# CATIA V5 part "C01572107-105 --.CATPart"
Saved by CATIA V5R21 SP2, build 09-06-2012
Part number: C01572107-105
Revision: ---
Description: PROPRIETARY NOTICE (do not delete / modify)  ***************************************************************************************************  LA SOCIETE EN COMMANDITE  AIRBUS CANADA  ("AIRBUS CANADA")  PAR  L'INTERMEDIAIRE  DE  SES  DIVISIONS  ET/OU  FILIALES  CORPORATIVES,  FOURNIT  LES PRESENTES  INFORMATIONS  AU  GOUVERNEMENT  A  TITRE CONFIDENTIEL. CES  INFORMATIONS ONT UNE TENEUR CONFIDENTIELLE,  AVEC DROITS DE PROPRIETE,  ET NOUS LES CONSIDERONS  EXCLUS  DE   L'APPLICATION  DE  LA LOI SUR L'ACCES A L'INFORMATION  (CANADA),  LES  LOIS  SUR  L'ACCES  A  L'INFORMATION  EUROPEENNES,  LE FREEDOM OF INFORMATION ACT (ETATS-UNIS) ET D'AUTRES LOIS SEMBLABLES. ELLES  PEUVENT  AUSSI  CONSTITUER DES SECRETS INDUSTRIELS DE NOTRE SOCIETE OU DE TIERCES PARTIES. LA DIVULGATION  PUBLIQUE  DE CES  INFORMATIONS NUIRAIT A AIRBUS CANADA OU A DES TIERCES PARTIES.  CES INFORMATIONS PEUVENT EGALEMENT CONTENIR  DES DONNEES QUI SONT CONTROLEE PAR DES LOIS DE CONTROLE DES EXPORTATIONS DU CANADA, L’EUROPE OU LES  ETATS-  UNIS. TOUTE EXPORTATION OU REEXPORTATION DE DONNEES CONTROLEES SANS AUTORISATION EST STRICTEMENT INTERDITE.  TOUTE INTENTION DE LES DIVULGUER EN TOUT OU EN PARTIE DEVRA ETRE SIGNIFIEE A L'AVANCE ET PAR ECRIT AU VICE-  PRESIDENT, SERVICES JURIDIQUES ET CONFORMITE ET SECRETAIRE CORPORATIF D'AIRBUS CANADA.    AIRBUS CANADA LIMITED PARTNERSHIP  ("AIRBUS CANADA"),  BY ITS AFFILIATES AND/OR SUBSIDIARIES, PROVIDES THIS  INFORMATION TO THE GOVERNMENT IN CONFIDENCE. THIS IS PROPRIETARY CONFIDENTIAL INFORMATION WHICH WE CONSIDER  EXCLUDED  FROM  THE  APPLICATION OF THE ACCESS TO INFORMATION ACT (CANADA),  THE FREEDOM OF INFORMATION ACT  (U.S.A.),  THE ACCESS TO INFORMATION LAWS IN EUROPE, AND OTHER SIMILAR LEGISLATION. AND MAY ALSO CONSTITUTE  TRADE SECRETS OF OUR  COMPANY OR THIRD PARTIES.  PUBLIC  RELEASE  OF  THIS INFORMATION  WOULD BE HARMFUL TO  AIRBUS CANADA OR THIRD PARTIES.  THIS  INFORMATION  MAY  ALSO  CONTAIN DATA THAT IS CONTROLLED BY CANADIAN,  EUROPEAN, OR U.S.A. EXPORT CONTROL LAWS. ANY UNAUTHORIZED EXPORT OR RE-EXPORT OF ANY EXPORT CONTROLLED DATA  IS STRICTLY PROHIBITED  ANY INTENTION TO DISCLOSE SUCH INFORMATION,  OR  PART THEREOF,  MUST BE NOTIFIED IN  ADVANCE AND IN WRITING TO THE VICE PRESIDENT, LEGAL AND COMPLIANCE AND CORPORATE SECRETARY OF AIRBUS CANADA.        LES RENSEIGNEMENTS,  LES DONNEES  ET  DESSINS  TECHNIQUES  DIVULGUES  DANS  LES PRESENTES SONT LA PROPRIETE  EXCLUSIVE DE LA SOCIETE EN COMMANDITE AIRBUS CANADA ("AIRBUS CANADA") OU COMPORTENT DES DROITS DE PROPRIETE  APPARTENANT  A  AUTRUI ET NE PEUVENT ETRE DIVULGUES  A  QUICONQUE  NI  UTILISES PAR QUI QUE CE SOIT SANS LE  CONSENTEMENT  ECRIT  D’AIRBUS  CANADA.  LE DETENTEUR DES  PRESENTES  S'ENGAGE, DANS TOUTES CIRCONSTANCES, A  GARDER CONFIDENTIELS LES DONNEES ET DESSINS TECHNIQUES QU'ELLES CONTIENNENT.   CE QUI PRECEDE NE S'APPLIQUE  PAS  AUX PERSONNES  QUI  ONT DES DROITS DE PROPRIETE SUR CES RENSEIGNEMENTS,  DONNEES TECHNIQUES ET DESSINS  DANS LA MESURE OU CES DROITS EXISTENT.    THE INFORMATION,  TECHNICAL DATA  AND  DESIGNS DISCLOSED HEREIN ARE THE EXCLUSIVE PROPERTY OF AIRBUS CANADA  LIMITED PARTNERSHIP  ("AIRBUS CANADA")  OR  CONTAIN PROPRIETARY RIGHTS OF OTHERS  AND ARE NOT TO BE USED OR  DISCLOSED  TO  OTHERS WITHOUT THE WRITTEN CONSENT OF AIRBUS CANADA.  THE RECIPIENT OF THIS DOCUMENT, BY ITS  RETENTION  AND  USE  AGREES TO  HOLD  IN  CONFIDENCE  THE  TECHNICAL DATA AND DESIGNS CONTAINED HEREIN. THE  FOREGOING SHALL NOT APPLY TO PERSONS HAVING PROPRIETARY RIGHTS TO SUCH INFORMATION,  TECHNICAL DATA OR SUCH  DESIGNS TO THE EXTENT THAT SUCH RIGHTS EXIST.    Copyright 2020 Airbus Canada Limited Partnership. All Rights Reserved.  ***********************************
Property "Title": "AXIS, TEE LINK, OWE"
Property "Dataset Type": "DETAIL"
Property "MFG Process": "MACHINED"
Property "Design Authority Program": "BD-500"
Property "Supplier Name And CAGE Code": "AIRBUS CANADA LIMITED PARTNERSHIP L0J48"
Property "Major Supplier Code": "LP"
Property "3D Only": "N/A"
Property "Dimensions": "DIMENSIONS ARE IN INCHES"
Property "Color Coded": "N/A"
Property "Roughness": "ALL MACHINED SURFACES 125 Ra MAX"
Property "Eng. Tolerances": "LINEAR .XX= +/-.03; .XXX= +/-.010; ANGULAR= +/-0.5 DEG"
Property "Tool Design Tolerances": "LINEAR .X= +/-.06; .XX= +/-.015; .XXX= +/-.005; .XXXX= +/-.001; ANGULAR= +/-0.5 DEG"
Property "Material Form": "BAR - ROUND"
Property "Finish Code": "S010"
Property "Wire Gauge": "-"
Property "Form": "N/A"
Property "Type": "N/A"
Property "Style": "N/A"
Property "Density": "N/A"
Property "Material Specification Production": "AMS5659"
Property "Material Description Production": "CRES"
Property "Alloy": "15-5PH"
Property "Material Class": "N/A"
Property "Grade/Composition": "N/A"
Property "Final Condition": "H1025"
Property "Standard Spec Die": "N/A"
Property "Mesh Cell Size": "N/A"
Property "PCCN": "2"
Property "Organization": "DESIGN"
Property "Length": 0
Property "Width": 0
Property "Inside Diameter": 0
Property "Outside Diameter": 0.75
Property "Wall": 0
Property "Thickness": 0
Property "Project": "BA"
Publications: "PartBody"
Material "CRES-PH-15-5-BAR": density 7833.41 kg/m3
Bounding box of the stored display mesh (mm): x -50.648 to 34.925, y -12.7 to 12.7, z -7.913 to 7.913
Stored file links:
  C:\Users\CQQZ006\Desktop\A220钢钛件\舱门\C01572107-105\C01572107-105 --.CATPart
  I:\Standard\Materials\Textures\steel100.jpeg

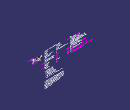
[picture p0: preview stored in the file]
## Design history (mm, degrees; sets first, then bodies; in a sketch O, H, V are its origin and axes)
AxisSystem1: origin (0, 0, 0), X (1, 0, 0), Y (0, 1, 0), Z (0, 0, 1)
TTRSSet1
Part_3D_Annotations1 "CATTPSSet"
Set1 "Pilot_Holes"
  Set2 "3/16\""
    Line1: type PtDir, RefPoint Intersect3, Direction ZX plane of AxisSystem1, Start -12.7, End 12.7
    Line2: type PtDir, RefPoint Intersect2, Direction ZX plane of AxisSystem1, Start -12.7, End 12.7
    Point1: type OnCurve, Support Line2, RefPoint Intersect2, Length 7.9134
    Point2: type OnCurve, Support Line1, RefPoint Intersect3, Length 7.9134
Set3 "References"
  Point3 "PILOT_HOLE_1_C01572103": stored without definition
  Point4 "PILOT_HOLE_2_C01572103": stored without definition
Set4 "Geometrical Set for 3D Annotations"
  Set5 "No Show Geometry"
    Extract1 "DATUM_B": ExtractElem face of Shaft1 from Sketch1.L5
    Extract2 "DATUM_A": ExtractElem face of Shaft1 from Sketch1.L2
    Extract3: ExtractElem face of Shaft1 from Sketch1.L4
  Set6 "Surfaces for 3D Annotations"
    Offset1: Offset Extract3, Length 0.0254
Set7 "Construction_Geometry"
  Set8 "Pilot_Holes_Const"
    Intersect1: ToIntersect1 zx-plane, ToIntersect2 xy-plane
    Plane1: type OffsetPt, RefPlane yz-plane, RefPoint Point3
    Plane2: type OffsetPt, RefPlane yz-plane, RefPoint Point4
    Intersect2: ToIntersect1 Intersect1, ToIntersect2 Plane1
    Intersect3: ToIntersect1 Intersect1, ToIntersect2 Plane2
Body1 (main body)
  Sketch1 on ZX plane of AxisSystem1, origin (0, 0, 0), H (1, 0, 0), V (0, 0, 1)
    axis line L1 (-67.8348, 0) -> (47.3294, 0)
    line L2 (-50.6476, 7.9134) -> (34.925, 7.9134)
    line L3 (34.925, 7.9134) -> (34.925, 6.35)
    line L4 (34.925, 6.35) -> (-50.6476, 6.35)
    line L5 (-50.6476, 6.35) -> (-50.6476, 7.9134)
    reference projected line E1 through (0, 0) direction (0, 1) from edge [ZX plane of AxisSystem1 | YZ plane of AxisSystem1]
    distance H L2 = 7.9134
    distance H L4 = 6.35
    distance L3 E1 = 34.925
    distance L5 V = 50.6476
    distance L3 L5 = 85.5726 (reference)
    coincidence: L1 H
    horizontal: L2 H, L4 H
    vertical: L3 V, L5 V
  Shaft1: profile Sketch1, axis Sketch1.L1, angle 360
  Chamfer1: length 0.762, second length 0.762, on edge [face of Shaft1 from Sketch1.L5 | face of Shaft1 from Sketch1.L2]; edge [face of Shaft1 from Sketch1.L2 | face of Shaft1 from Sketch1.L3]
